VERSION 5.4 ;
NAMESCASESENSITIVE ON ;
BUSBITCHARS "[]" ;
DIVIDERCHAR "/" ;
UNITS
  DATABASE MICRONS 2000 ;
END UNITS
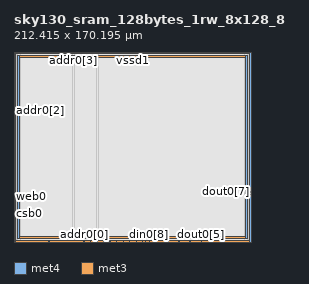
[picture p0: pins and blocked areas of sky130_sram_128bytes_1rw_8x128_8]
MACRO sky130_sram_128bytes_1rw_8x128_8
   CLASS BLOCK ;
   SIZE 212.415 BY 170.195 ;
   SYMMETRY X Y R90 ;
   PIN din0[0]
      DIRECTION INPUT ;
      PORT
         LAYER met4 ;
         RECT  74.28 0.0 74.66 0.38 ;
      END
   END din0[0]
   PIN din0[1]
      DIRECTION INPUT ;
      PORT
         LAYER met4 ;
         RECT  80.12 0.0 80.5 0.38 ;
      END
   END din0[1]
   PIN din0[2]
      DIRECTION INPUT ;
      PORT
         LAYER met4 ;
         RECT  85.96 0.0 86.34 0.38 ;
      END
   END din0[2]
   PIN din0[3]
      DIRECTION INPUT ;
      PORT
         LAYER met4 ;
         RECT  91.8 0.0 92.18 0.38 ;
      END
   END din0[3]
   PIN din0[4]
      DIRECTION INPUT ;
      PORT
         LAYER met4 ;
         RECT  97.64 0.0 98.02 0.38 ;
      END
   END din0[4]
   PIN din0[5]
      DIRECTION INPUT ;
      PORT
         LAYER met4 ;
         RECT  103.48 0.0 103.86 0.38 ;
      END
   END din0[5]
   PIN din0[6]
      DIRECTION INPUT ;
      PORT
         LAYER met4 ;
         RECT  109.32 0.0 109.7 0.38 ;
      END
   END din0[6]
   PIN din0[7]
      DIRECTION INPUT ;
      PORT
         LAYER met4 ;
         RECT  115.16 0.0 115.54 0.38 ;
      END
   END din0[7]
   PIN din0[8]
      DIRECTION INPUT ;
      PORT
         LAYER met4 ;
         RECT  121.0 0.0 121.38 0.38 ;
      END
   END din0[8]
   PIN addr0[0]
      DIRECTION INPUT ;
      PORT
         LAYER met4 ;
         RECT  62.6 0.0 62.98 0.38 ;
      END
   END addr0[0]
   PIN addr0[1]
      DIRECTION INPUT ;
      PORT
         LAYER met4 ;
         RECT  68.44 0.0 68.82 0.38 ;
      END
   END addr0[1]
   PIN addr0[2]
      DIRECTION INPUT ;
      PORT
         LAYER met3 ;
         RECT  0.0 117.985 0.38 118.365 ;
      END
   END addr0[2]
   PIN addr0[3]
      DIRECTION INPUT ;
      PORT
         LAYER met4 ;
         RECT  53.045 169.815 53.425 170.195 ;
      END
   END addr0[3]
   PIN addr0[4]
      DIRECTION INPUT ;
      PORT
         LAYER met4 ;
         RECT  49.38 169.815 49.76 170.195 ;
      END
   END addr0[4]
   PIN addr0[5]
      DIRECTION INPUT ;
      PORT
         LAYER met4 ;
         RECT  52.355 169.815 52.735 170.195 ;
      END
   END addr0[5]
   PIN addr0[6]
      DIRECTION INPUT ;
      PORT
         LAYER met4 ;
         RECT  51.665 169.815 52.045 170.195 ;
      END
   END addr0[6]
   PIN addr0[7]
      DIRECTION INPUT ;
      PORT
         LAYER met4 ;
         RECT  50.92 169.815 51.3 170.195 ;
      END
   END addr0[7]
   PIN csb0
      DIRECTION INPUT ;
      PORT
         LAYER met3 ;
         RECT  0.0 25.455 0.38 25.835 ;
      END
   END csb0
   PIN web0
      DIRECTION INPUT ;
      PORT
         LAYER met3 ;
         RECT  0.0 33.955 0.38 34.335 ;
      END
   END web0
   PIN clk0
      DIRECTION INPUT ;
      PORT
         LAYER met4 ;
         RECT  31.1 0.0 31.48 0.38 ;
      END
   END clk0
   PIN spare_wen0
      DIRECTION INPUT ;
      PORT
         LAYER met4 ;
         RECT  126.84 0.0 127.22 0.38 ;
      END
   END spare_wen0
   PIN dout0[0]
      DIRECTION OUTPUT ;
      PORT
         LAYER met4 ;
         RECT  117.64 0.0 118.02 0.38 ;
      END
   END dout0[0]
   PIN dout0[1]
      DIRECTION OUTPUT ;
      PORT
         LAYER met4 ;
         RECT  127.64 0.0 128.02 0.38 ;
      END
   END dout0[1]
   PIN dout0[2]
      DIRECTION OUTPUT ;
      PORT
         LAYER met4 ;
         RECT  137.64 0.0 138.02 0.38 ;
      END
   END dout0[2]
   PIN dout0[3]
      DIRECTION OUTPUT ;
      PORT
         LAYER met4 ;
         RECT  147.64 0.0 148.02 0.38 ;
      END
   END dout0[3]
   PIN dout0[4]
      DIRECTION OUTPUT ;
      PORT
         LAYER met4 ;
         RECT  157.64 0.0 158.02 0.38 ;
      END
   END dout0[4]
   PIN dout0[5]
      DIRECTION OUTPUT ;
      PORT
         LAYER met4 ;
         RECT  167.64 0.0 168.02 0.38 ;
      END
   END dout0[5]
   PIN dout0[6]
      DIRECTION OUTPUT ;
      PORT
         LAYER met3 ;
         RECT  212.035 42.385 212.415 42.765 ;
      END
   END dout0[6]
   PIN dout0[7]
      DIRECTION OUTPUT ;
      PORT
         LAYER met3 ;
         RECT  212.035 44.975 212.415 45.355 ;
      END
   END dout0[7]
   PIN dout0[8]
      DIRECTION OUTPUT ;
      PORT
         LAYER met3 ;
         RECT  212.035 44.23 212.415 44.61 ;
      END
   END dout0[8]
   PIN vccd1
      DIRECTION INOUT ;
      USE POWER ; 
      SHAPE ABUTMENT ; 
      PORT
         LAYER met4 ;
         RECT  210.675 0.0 212.415 170.195 ;
         LAYER met3 ;
         RECT  0.0 0.0 212.415 1.74 ;
         LAYER met3 ;
         RECT  0.0 168.455 212.415 170.195 ;
         LAYER met4 ;
         RECT  0.0 0.0 1.74 170.195 ;
      END
   END vccd1
   PIN vssd1
      DIRECTION INOUT ;
      USE GROUND ; 
      SHAPE ABUTMENT ; 
      PORT
         LAYER met4 ;
         RECT  3.48 3.48 5.22 166.715 ;
         LAYER met3 ;
         RECT  3.48 3.48 208.935 5.22 ;
         LAYER met3 ;
         RECT  3.48 164.975 208.935 166.715 ;
         LAYER met4 ;
         RECT  207.195 3.48 208.935 166.715 ;
      END
   END vssd1
   OBS
   LAYER  met1 ;
      RECT  0.62 0.62 211.795 169.575 ;
   LAYER  met2 ;
      RECT  0.62 0.62 211.795 169.575 ;
   LAYER  met3 ;
      RECT  0.98 117.385 211.795 118.965 ;
      RECT  0.62 26.435 0.98 33.355 ;
      RECT  0.62 34.935 0.98 117.385 ;
      RECT  0.98 41.785 211.435 43.365 ;
      RECT  0.98 43.365 211.435 117.385 ;
      RECT  211.435 45.955 211.795 117.385 ;
      RECT  211.435 43.365 211.795 43.63 ;
      RECT  0.62 2.34 0.98 24.855 ;
      RECT  211.435 2.34 211.795 41.785 ;
      RECT  0.62 118.965 0.98 167.855 ;
      RECT  0.98 2.34 2.88 2.88 ;
      RECT  0.98 2.88 2.88 5.82 ;
      RECT  0.98 5.82 2.88 41.785 ;
      RECT  2.88 2.34 209.535 2.88 ;
      RECT  2.88 5.82 209.535 41.785 ;
      RECT  209.535 2.34 211.435 2.88 ;
      RECT  209.535 2.88 211.435 5.82 ;
      RECT  209.535 5.82 211.435 41.785 ;
      RECT  0.98 118.965 2.88 164.375 ;
      RECT  0.98 164.375 2.88 167.315 ;
      RECT  0.98 167.315 2.88 167.855 ;
      RECT  2.88 118.965 209.535 164.375 ;
      RECT  2.88 167.315 209.535 167.855 ;
      RECT  209.535 118.965 211.795 164.375 ;
      RECT  209.535 164.375 211.795 167.315 ;
      RECT  209.535 167.315 211.795 167.855 ;
   LAYER  met4 ;
      RECT  73.68 0.98 75.26 169.575 ;
      RECT  75.26 0.62 79.52 0.98 ;
      RECT  81.1 0.62 85.36 0.98 ;
      RECT  86.94 0.62 91.2 0.98 ;
      RECT  92.78 0.62 97.04 0.98 ;
      RECT  98.62 0.62 102.88 0.98 ;
      RECT  104.46 0.62 108.72 0.98 ;
      RECT  110.3 0.62 114.56 0.98 ;
      RECT  63.58 0.62 67.84 0.98 ;
      RECT  69.42 0.62 73.68 0.98 ;
      RECT  52.445 0.98 54.025 169.215 ;
      RECT  54.025 0.98 73.68 169.215 ;
      RECT  54.025 169.215 73.68 169.575 ;
      RECT  32.08 0.62 62.0 0.98 ;
      RECT  121.98 0.62 126.24 0.98 ;
      RECT  116.14 0.62 117.04 0.98 ;
      RECT  118.62 0.62 120.4 0.98 ;
      RECT  128.62 0.62 137.04 0.98 ;
      RECT  138.62 0.62 147.04 0.98 ;
      RECT  148.62 0.62 157.04 0.98 ;
      RECT  158.62 0.62 167.04 0.98 ;
      RECT  168.62 0.62 210.075 0.98 ;
      RECT  2.34 169.215 48.78 169.575 ;
      RECT  2.34 0.62 30.5 0.98 ;
      RECT  2.34 0.98 2.88 2.88 ;
      RECT  2.34 2.88 2.88 167.315 ;
      RECT  2.34 167.315 2.88 169.215 ;
      RECT  2.88 0.98 5.82 2.88 ;
      RECT  2.88 167.315 5.82 169.215 ;
      RECT  5.82 0.98 52.445 2.88 ;
      RECT  5.82 2.88 52.445 167.315 ;
      RECT  5.82 167.315 52.445 169.215 ;
      RECT  75.26 0.98 206.595 2.88 ;
      RECT  75.26 2.88 206.595 167.315 ;
      RECT  75.26 167.315 206.595 169.575 ;
      RECT  206.595 0.98 209.535 2.88 ;
      RECT  206.595 167.315 209.535 169.575 ;
      RECT  209.535 0.98 210.075 2.88 ;
      RECT  209.535 2.88 210.075 167.315 ;
      RECT  209.535 167.315 210.075 169.575 ;
   END
END    sky130_sram_128bytes_1rw_8x128_8
END    LIBRARY
